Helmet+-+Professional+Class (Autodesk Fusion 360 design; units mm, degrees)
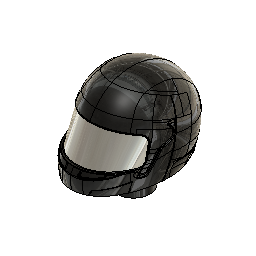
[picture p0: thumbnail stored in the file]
description: STEP AP214
part number: Bell Helmet with dowel
base_feature "Base Feature"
